! (c) 2009  Infineon Technologies AG, Munich
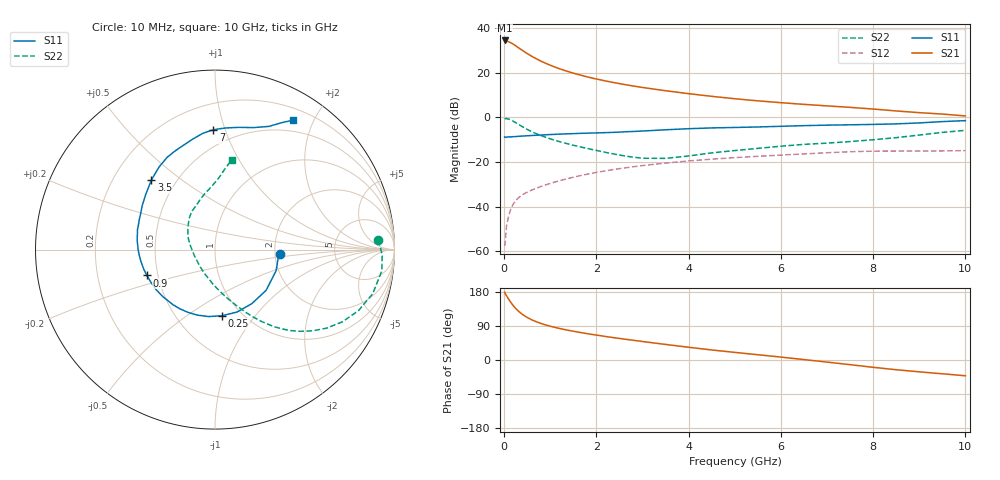
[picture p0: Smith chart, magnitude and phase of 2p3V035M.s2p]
! Infineon Technologies  Discrete & RF Semiconductors
! BFP420
! VCE =  3.0 V,  IC =  35 mA
! Common Emitter S-Parameters:  Nov 2009
# GHz  S  MA  R  50
!  f  S11  S21  S12  S22
! GHz  MAG  ANG  MAG  ANG  MAG  ANG  MAG  ANG
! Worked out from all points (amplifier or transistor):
!   46 points, 10 MHz to 10 GHz, reference 50 ohm
!   highest |S21| = 34.4 dB at 10 MHz (marker M1)
!   |S21| within 3 dB of that: start of sweep to 292.7 MHz
!   unconditionally stable (mu >= 1): start of sweep to 12.98 MHz; 1.457 GHz to end of sweep
!   at 300 MHz: K = 0.43, MSG = 33.8 dB, |S12| = -36.2 dB
!   at 1.7 GHz: K = 1.04, MAG = 21.1 dB, |S12| = -25.9 dB
!   at 10 GHz: K = 1.06, MAG = 6.3 dB, |S12| = -14.9 dB
!   lowest NFmin = 1.64 dB at 900 MHz
!   S11 on the Smith chart (normalised r, x): 10 MHz: 2.13, -0.11; 250 MHz: 0.81, -0.70; 900 MHz: 0.43, -0.15; 3.5 GHz: 0.36, +0.39; 7 GHz: 0.38, +0.91; 10 GHz: 0.35, +1.72
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0.01  0.3623 -3.7  52.67 179.0  0.0013 87.2  0.9122 3.4
0.02  0.3552 -8.0  51.51 175.8  0.0015 91.4  0.9322 -1.9
0.05  0.3602 -19.2  50.92 169.8  0.0036 82.6  0.937 -7.2
0.1  0.3641 -38.6  49.27 160.1  0.0063 78.7  0.9127 -15.6
0.15  0.3645 -55.8  46.48 151.1  0.0092 73.7  0.8685 -23.1
0.2  0.369 -70.6  43.32 143.2  0.0115 70.1  0.8154 -29.6
0.25  0.3704 -84.0  39.92 136.1  0.0136 67.3  0.7608 -35.1
0.3  0.3747 -95.4  36.86 130.0  0.0154 64.9  0.7073 -39.8
0.35  0.378 -105.1  33.94 124.7  0.017 63.3  0.6578 -43.8
0.4  0.3807 -113.4  31.3 120.0  0.0185 62.0  0.6132 -47.3
0.5  0.386 -127.1  26.8 112.3  0.0211 60.5  0.5371 -52.8
0.6  0.3913 -137.8  23.23 105.9  0.0235 59.9  0.477 -57.1
0.7  0.3972 -146.2  20.39 100.8  0.0259 59.6  0.4289 -60.7
0.9  0.406 -159.2  16.23 92.5  0.0307 59.6  0.3577 -66.6
1.3  0.4242 -176.7  11.3 80.6  0.0405 59.0  0.2677 -77.3
1.7  0.4388 170.9  8.573 71.6  0.0507 57.3  0.2118 -88.2
2.4  0.4614 153.6  5.941 58.6  0.0684 52.3  0.1492 -110.9
3.5  0.5259 132.3  3.937 41.1  0.0944 42.3  0.1203 -165.4
5.5  0.6081 106.6  2.339 13.9  0.1338 23.3  0.2017 137.9
7  0.668 90.8  1.803 -5.5  0.1609 9.0  0.2642 114.3
8.5  0.7131 72.4  1.389 -25.7  0.1753 -8.2  0.3505 93.3
10  0.8432 58.8  1.073 -41.6  0.179 -19.6  0.5104 79.3
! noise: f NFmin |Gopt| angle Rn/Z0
0.9  1.64  0.3  -155  0.13
1.8  1.9  0.37  -142  0.15
2.4  2.1  0.34  -134  0.19
3  2.11  0.4  -126  0.22
4  2.25  0.5  -110  0.35
5  2.73  0.54  -94  0.59
6  3.16  0.59  -82  0.84
